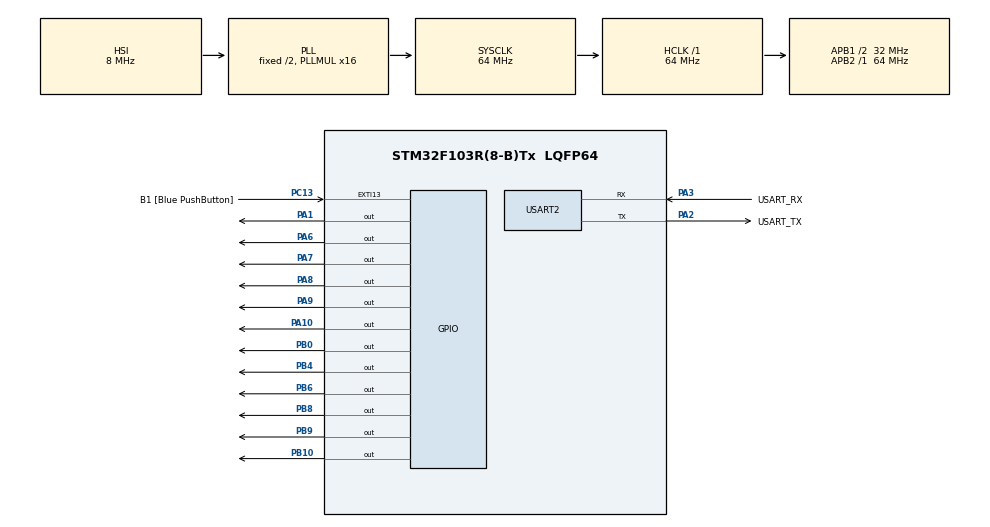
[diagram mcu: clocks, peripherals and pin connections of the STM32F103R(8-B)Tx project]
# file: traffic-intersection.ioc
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FREERTOS.Mutexes01=stateMachine,Dynamic,NULL,Available;statePeriod,Dynamic,NULL,Available
FREERTOS.Tasks01=stateHandler,24,128,StartStateHandler,Default,NULL,Dynamic,NULL,NULL;updateCLI,8,128,StartUpdateCLI,Default,NULL,Dynamic,NULL,NULL;startCLIIT,16,128,StartCLIInterrupt,Default,NULL,Dynamic,NULL,NULL;blinkDirection,8,128,StartBlinkDirection,Default,NULL,Dynamic,NULL,NULL
FREERTOS.configUSE_NEWLIB_REENTRANT=1
Mcu.Family=STM32F1
Mcu.Name=STM32F103R(8-B)Tx
Mcu.Package=LQFP64
NVIC.EXTI15_10_IRQn=true\:5\:0\:false\:false\:true\:true\:true\:true\:true
NVIC.PriorityGroup=NVIC_PRIORITYGROUP_4
NVIC.TIM3_IRQn=true\:15\:0\:false\:false\:true\:false\:false\:true\:true
NVIC.TimeBase=TIM3_IRQn
NVIC.TimeBaseIP=TIM3
NVIC.USART2_IRQn=true\:5\:0\:false\:false\:true\:true\:true\:true\:true
PA1.GPIO_PuPd=GPIO_PULLDOWN
PA1.Signal=GPIO_Output
PA10.GPIO_PuPd=GPIO_PULLDOWN
PA10.Signal=GPIO_Output
PA13.GPIO_Label=TMS
PA13.Mode=Serial_Wire
PA13.Signal=SYS_JTMS-SWDIO
PA14.GPIO_Label=TCK
PA14.Mode=Serial_Wire
PA14.Signal=SYS_JTCK-SWCLK
PA2.GPIO_Label=USART_TX
PA2.GPIO_Mode=GPIO_MODE_AF_PP
PA2.GPIO_PuPd=GPIO_NOPULL
PA2.GPIO_Speed=GPIO_SPEED_FREQ_LOW
PA2.Mode=Asynchronous
PA2.Signal=USART2_TX
PA3.GPIO_Label=USART_RX
PA3.GPIO_Mode=GPIO_MODE_AF_PP
PA3.GPIO_PuPd=GPIO_NOPULL
PA3.GPIO_Speed=GPIO_SPEED_FREQ_LOW
PA3.Mode=Asynchronous
PA3.Signal=USART2_RX
PA6.GPIO_PuPd=GPIO_PULLDOWN
PA6.Signal=GPIO_Output
PA7.GPIO_PuPd=GPIO_PULLDOWN
PA7.Signal=GPIO_Output
PA8.GPIO_PuPd=GPIO_PULLDOWN
PA8.Signal=GPIO_Output
PA9.GPIO_PuPd=GPIO_PULLDOWN
PA9.Signal=GPIO_Output
PB0.GPIO_PuPd=GPIO_PULLDOWN
PB0.Signal=GPIO_Output
PB10.GPIO_PuPd=GPIO_PULLDOWN
PB10.Signal=GPIO_Output
PB3.GPIO_Label=SWO
PB3.Signal=SYS_JTDO-TRACESWO
PB4.GPIO_PuPd=GPIO_PULLDOWN
PB4.Signal=GPIO_Output
PB6.GPIO_PuPd=GPIO_PULLDOWN
PB6.Signal=GPIO_Output
PB8.GPIO_PuPd=GPIO_PULLDOWN
PB8.Signal=GPIO_Output
PB9.GPIO_PuPd=GPIO_PULLDOWN
PB9.Signal=GPIO_Output
PC13-TAMPER-RTC.GPIO_Label=B1 [Blue PushButton]
PC13-TAMPER-RTC.GPIO_PuPd=GPIO_NOPULL
PC13-TAMPER-RTC.Signal=GPXTI13
PC14-OSC32_IN.Mode=LSE-External-Oscillator
PC14-OSC32_IN.Signal=RCC_OSC32_IN
PC15-OSC32_OUT.Mode=LSE-External-Oscillator
PC15-OSC32_OUT.Signal=RCC_OSC32_OUT
PD0-OSC_IN.Mode=HSE-External-Clock-Source
PD0-OSC_IN.Signal=RCC_OSC_IN
PD1-OSC_OUT.Mode=HSE-External-Clock-Source
PD1-OSC_OUT.Signal=RCC_OSC_OUT
ProjectManager.HeapSize=0x200
ProjectManager.StackSize=0x400
ProjectManager.TargetToolchain=STM32CubeIDE
RCC.AHBFreq_Value=64000000
RCC.APB1CLKDivider=RCC_HCLK_DIV2
RCC.APB1Freq_Value=32000000
RCC.APB1TimFreq_Value=64000000
RCC.APB2Freq_Value=64000000
RCC.APB2TimFreq_Value=64000000
RCC.HCLKFreq_Value=64000000
RCC.PLLMUL=RCC_PLL_MUL16
RCC.RTCClockSelection=RCC_RTCCLKSOURCE_LSE
RCC.SYSCLKFreq_VALUE=64000000
RCC.SYSCLKSource=RCC_SYSCLKSOURCE_PLLCLK
RCC.USBFreq_Value=64000000
USART2.VirtualMode=VM_ASYNC
VP_FREERTOS_VS_CMSIS_V2.Mode=CMSIS_V2
VP_SYS_VS_tim3.Mode=TIM3
board=NUCLEO-F103RB

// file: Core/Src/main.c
/* USER CODE BEGIN Header */
/**
  ******************************************************************************
  * @file           : main.c
  * @brief          : Main program body
  ******************************************************************************
  * @attention
  *
  * Copyright (c) 2024 STMicroelectronics.
  * All rights reserved.
  *
  * This software is licensed under terms that can be found in the LICENSE file
  * in the root directory of this software component.
  * If no LICENSE file comes with this software, it is provided AS-IS.
  *
  ******************************************************************************
  */
/* USER CODE END Header */
#include "main.h"
#include "cmsis_os.h"

/* USER CODE BEGIN Includes */
#include "task.h" // vTaskSuspend used in task startCLIIT
/* USER CODE END Includes */

UART_HandleTypeDef huart2;

/* Definitions for stateHandler */
osThreadId_t stateHandlerHandle;
const osThreadAttr_t stateHandler_attributes = {
  .name = "stateHandler",
  .stack_size = 128 * 4,
  .priority = (osPriority_t) osPriorityNormal,
};
/* Definitions for updateCLI */
osThreadId_t updateCLIHandle;
const osThreadAttr_t updateCLI_attributes = {
  .name = "updateCLI",
  .stack_size = 128 * 4,
  .priority = (osPriority_t) osPriorityLow,
};
/* Definitions for startCLIIT */
osThreadId_t startCLIITHandle;
const osThreadAttr_t startCLIIT_attributes = {
  .name = "startCLIIT",
  .stack_size = 128 * 4,
  .priority = (osPriority_t) osPriorityBelowNormal,
};
/* Definitions for blinkDirection */
osThreadId_t blinkDirectionHandle;
const osThreadAttr_t blinkDirection_attributes = {
  .name = "blinkDirection",
  .stack_size = 128 * 4,
  .priority = (osPriority_t) osPriorityLow,
};
/* Definitions for stateMachine */
osMutexId_t stateMachineHandle;
const osMutexAttr_t stateMachine_attributes = {
  .name = "stateMachine"
};
/* Definitions for statePeriod */
osMutexId_t statePeriodHandle;
const osMutexAttr_t statePeriod_attributes = {
  .name = "statePeriod"
};
/* USER CODE BEGIN PV */
volatile uint16_t period = 400;

uint8_t RXChar;			// input character from HAL_UART_Receive

HAL_StatusTypeDef status; // HAL_OK, HAL_ERROR, HAL_BUSY, HAL_TIMEOUT
/* USER CODE END PV */

void SystemClock_Config(void);
static void MX_GPIO_Init(void);
static void MX_USART2_UART_Init(void);
void StartStateHandler(void *argument);
void StartUpdateCLI(void *argument);
void StartCLIInterrupt(void *argument);
void StartBlinkDirection(void *argument);

/* USER CODE BEGIN 0 */
/**
  * @brief process a receiving character from USART
  *        The goal is to keep the function as fast as possible
  *        and to delegate the slow tasks like transmission
  *        to RTOS tasks to increase the availability of the
  *        function to serve the next interrupt
  * @param huart:  handler to USART2 ( the only used one - no need to check)
  * @retval None
  */
/* USER CODE END 0 */

int main(void)
{

  /* MCU Configuration--------------------------------------------------------*/

  /* Reset of all peripherals, Initializes the Flash interface and the Systick. */
  HAL_Init();

  /* Configure the system clock */
  SystemClock_Config();

  /* Initialize all configured peripherals */
  MX_GPIO_Init();
  MX_USART2_UART_Init();

  /* Init scheduler */
  osKernelInitialize();
  /* Create the mutex(es) */
  /* creation of stateMachine */
  stateMachineHandle = osMutexNew(&stateMachine_attributes);

  /* creation of statePeriod */
  statePeriodHandle = osMutexNew(&statePeriod_attributes);

  /* Create the thread(s) */
  /* creation of stateHandler */
  stateHandlerHandle = osThreadNew(StartStateHandler, NULL, &stateHandler_attributes);

  /* creation of updateCLI */
  updateCLIHandle = osThreadNew(StartUpdateCLI, NULL, &updateCLI_attributes);

  /* creation of startCLIIT */
  startCLIITHandle = osThreadNew(StartCLIInterrupt, NULL, &startCLIIT_attributes);

  /* creation of blinkDirection */
  blinkDirectionHandle = osThreadNew(StartBlinkDirection, NULL, &blinkDirection_attributes);

  /* Start scheduler */
  osKernelStart();

  /* We should never get here as control is now taken by the scheduler */

  /* Infinite loop */
  while (1)
  {

  }
}

void SystemClock_Config(void)
{
  RCC_OscInitTypeDef RCC_OscInitStruct = {0};
  RCC_ClkInitTypeDef RCC_ClkInitStruct = {0};

  /** Initializes the RCC Oscillators according to the specified parameters
  * in the RCC_OscInitTypeDef structure.
  */
  RCC_OscInitStruct.OscillatorType = RCC_OSCILLATORTYPE_HSI;
  RCC_OscInitStruct.HSIState = RCC_HSI_ON;
  RCC_OscInitStruct.HSICalibrationValue = RCC_HSICALIBRATION_DEFAULT;
  RCC_OscInitStruct.PLL.PLLState = RCC_PLL_ON;
  RCC_OscInitStruct.PLL.PLLSource = RCC_PLLSOURCE_HSI_DIV2;
  RCC_OscInitStruct.PLL.PLLMUL = RCC_PLL_MUL16;
  if (HAL_RCC_OscConfig(&RCC_OscInitStruct) != HAL_OK)
  {
    Error_Handler();
  }

  /** Initializes the CPU, AHB and APB buses clocks
  */
  RCC_ClkInitStruct.ClockType = RCC_CLOCKTYPE_HCLK|RCC_CLOCKTYPE_SYSCLK
                              |RCC_CLOCKTYPE_PCLK1|RCC_CLOCKTYPE_PCLK2;
  RCC_ClkInitStruct.SYSCLKSource = RCC_SYSCLKSOURCE_PLLCLK;
  RCC_ClkInitStruct.AHBCLKDivider = RCC_SYSCLK_DIV1;
  RCC_ClkInitStruct.APB1CLKDivider = RCC_HCLK_DIV2;
  RCC_ClkInitStruct.APB2CLKDivider = RCC_HCLK_DIV1;

  if (HAL_RCC_ClockConfig(&RCC_ClkInitStruct, FLASH_LATENCY_2) != HAL_OK)
  {
    Error_Handler();
  }
}

static void MX_USART2_UART_Init(void)
{

  huart2.Instance = USART2;
  huart2.Init.BaudRate = 115200;
  huart2.Init.WordLength = UART_WORDLENGTH_8B;
  huart2.Init.StopBits = UART_STOPBITS_1;
  huart2.Init.Parity = UART_PARITY_NONE;
  huart2.Init.Mode = UART_MODE_TX_RX;
  huart2.Init.HwFlowCtl = UART_HWCONTROL_NONE;
  huart2.Init.OverSampling = UART_OVERSAMPLING_16;
  if (HAL_UART_Init(&huart2) != HAL_OK)
  {
    Error_Handler();
  }

}

static void MX_GPIO_Init(void)
{
  GPIO_InitTypeDef GPIO_InitStruct = {0};

  /* GPIO Ports Clock Enable */
  __HAL_RCC_GPIOC_CLK_ENABLE();
  __HAL_RCC_GPIOD_CLK_ENABLE();
  __HAL_RCC_GPIOA_CLK_ENABLE();
  __HAL_RCC_GPIOB_CLK_ENABLE();

  /*Configure GPIO pin Output Level */
  HAL_GPIO_WritePin(GPIOA, GPIO_PIN_1|GPIO_PIN_6|GPIO_PIN_7|GPIO_PIN_8
                          |GPIO_PIN_9|GPIO_PIN_10, GPIO_PIN_RESET);

  /*Configure GPIO pin Output Level */
  HAL_GPIO_WritePin(GPIOB, GPIO_PIN_0|GPIO_PIN_10|GPIO_PIN_4|GPIO_PIN_6
                          |GPIO_PIN_8|GPIO_PIN_9, GPIO_PIN_RESET);

  /*Configure GPIO pin : B1_Pin */
  GPIO_InitStruct.Pin = B1_Pin;
  GPIO_InitStruct.Mode = GPIO_MODE_IT_RISING;
  GPIO_InitStruct.Pull = GPIO_NOPULL;
  HAL_GPIO_Init(B1_GPIO_Port, &GPIO_InitStruct);

  /*Configure GPIO pins : PC0 PC1 */
  GPIO_InitStruct.Pin = GPIO_PIN_0|GPIO_PIN_1;
  GPIO_InitStruct.Mode = GPIO_MODE_IT_RISING;
  GPIO_InitStruct.Pull = GPIO_PULLUP;
  HAL_GPIO_Init(GPIOC, &GPIO_InitStruct);

  /*Configure GPIO pins : PA1 PA6 PA7 PA8
                           PA9 PA10 */
  GPIO_InitStruct.Pin = GPIO_PIN_1|GPIO_PIN_6|GPIO_PIN_7|GPIO_PIN_8
                          |GPIO_PIN_9|GPIO_PIN_10;
  GPIO_InitStruct.Mode = GPIO_MODE_OUTPUT_PP;
  GPIO_InitStruct.Pull = GPIO_PULLDOWN;
  GPIO_InitStruct.Speed = GPIO_SPEED_FREQ_LOW;
  HAL_GPIO_Init(GPIOA, &GPIO_InitStruct);

  /*Configure GPIO pins : PB0 PB10 PB4 PB6
                           PB8 PB9 */
  GPIO_InitStruct.Pin = GPIO_PIN_0|GPIO_PIN_10|GPIO_PIN_4|GPIO_PIN_6
                          |GPIO_PIN_8|GPIO_PIN_9;
  GPIO_InitStruct.Mode = GPIO_MODE_OUTPUT_PP;
  GPIO_InitStruct.Pull = GPIO_PULLDOWN;
  GPIO_InitStruct.Speed = GPIO_SPEED_FREQ_LOW;
  HAL_GPIO_Init(GPIOB, &GPIO_InitStruct);

  /* EXTI interrupt init*/
  HAL_NVIC_SetPriority(EXTI0_IRQn, 5, 0);
  HAL_NVIC_EnableIRQ(EXTI0_IRQn);

  HAL_NVIC_SetPriority(EXTI1_IRQn, 5, 0);
  HAL_NVIC_EnableIRQ(EXTI1_IRQn);

  HAL_NVIC_SetPriority(EXTI15_10_IRQn, 5, 0);
  HAL_NVIC_EnableIRQ(EXTI15_10_IRQn);

}

/* USER CODE BEGIN 4 */
void HAL_UART_RxCpltCallback(UART_HandleTypeDef *huart)
{
	// process input string
	HandleInput(huart, RXChar);

	// wait until status is ok
	while((HAL_UART_GetState(huart)&HAL_UART_STATE_BUSY_RX)
			== HAL_UART_STATE_BUSY_RX);
	//Listen for the interrupt and buffer one character at a time.
	status = HAL_UART_Receive_IT(huart, &RXChar, 1);
	if (status != HAL_OK)
	{
		Error_Handler();
	}

	return;
}

void HAL_UART_TxCpltCallback(UART_HandleTypeDef *huart)
{
	// do nothing! :O
}

void HAL_GPIO_EXTI_Callback(uint16_t GPIO_Pin)
{
	/*
	 * No debounce is needed as this simply sets a flag to 1,
	 * to be unset later when the state changes to GREEN_WALK
	 * for a given direction
	 */
	if (GPIO_Pin == GPIO_PIN_0)
	{ // PC0 for NS crosswalk
		SetCrosswalkFlag("N");
	}
	else if (GPIO_Pin == GPIO_PIN_1)
	{ // PC1 for EW crosswalk
		SetCrosswalkFlag("E");
	}
}
/* USER CODE END 4 */

void StartStateHandler(void *argument)
{
  /* USER CODE BEGIN 5 */
	/* Infinite loop */
	for(;;)
	{

		ChangeState((current_state + 1) % 6); // 6 normal states of operation
		RefreshStatus(&huart2);
		// current_state is updated after calling ChangeState()
		osDelay(state_periods[current_state]);
	}
  /* USER CODE END 5 */
}

void StartUpdateCLI(void *argument)
{
  /* USER CODE BEGIN StartUpdateCLI */
	/* Infinite loop */
	for(;;)
	{
		RefreshStatus(&huart2);
		osDelay(500);
	}
  /* USER CODE END StartUpdateCLI */
}

void StartCLIInterrupt(void *argument)
{
  /* USER CODE BEGIN StartCLIInterrupt */
	// initialize CLI
	 CLIInit(&huart2);

	// begin receiving characters through UART
	// interrupt callback restarts the Receive_IT call
	HAL_UART_Receive_IT(&huart2, &RXChar, 1);

	// suspend task as the utility is handled
	// by the interrupt callback
	vTaskSuspend(NULL);
  /* USER CODE END StartCLIInterrupt */
}

void StartBlinkDirection(void *argument)
{
  /* USER CODE BEGIN StartBlinkDirection */
	// TODO: 	refactor to use an LED provided from argument
	//			rather than figuring it out from a given direction
	Direction direction = *((Direction *) argument);

	/* Infinite loop */
	for(;;)
	{
	osDelay(1);
	}
  /* USER CODE END StartBlinkDirection */
}

void HAL_TIM_PeriodElapsedCallback(TIM_HandleTypeDef *htim)
{
  if (htim->Instance == TIM3) {
    HAL_IncTick();
  }
}

void Error_Handler(void)
{
  __disable_irq();
  while (1)
  {
  }
}
